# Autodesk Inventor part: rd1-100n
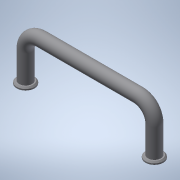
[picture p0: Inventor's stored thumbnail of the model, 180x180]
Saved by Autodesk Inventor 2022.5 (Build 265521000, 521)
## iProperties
Created: 2016-12
Part Number: rd1-100n
Material: 一般
Document SubType Name: Modeling
Designer: imaocorp
Density: 1 g/cm^3
Appearance: 既定
Author: imaocorp
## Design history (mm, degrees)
node "rd1-100n.x_t1"
node "rd1-100n"
node "Base1"
